VERSION 5.7 ;
  NOWIREEXTENSIONATPIN ON ;
  DIVIDERCHAR "/" ;
  BUSBITCHARS "[]" ;
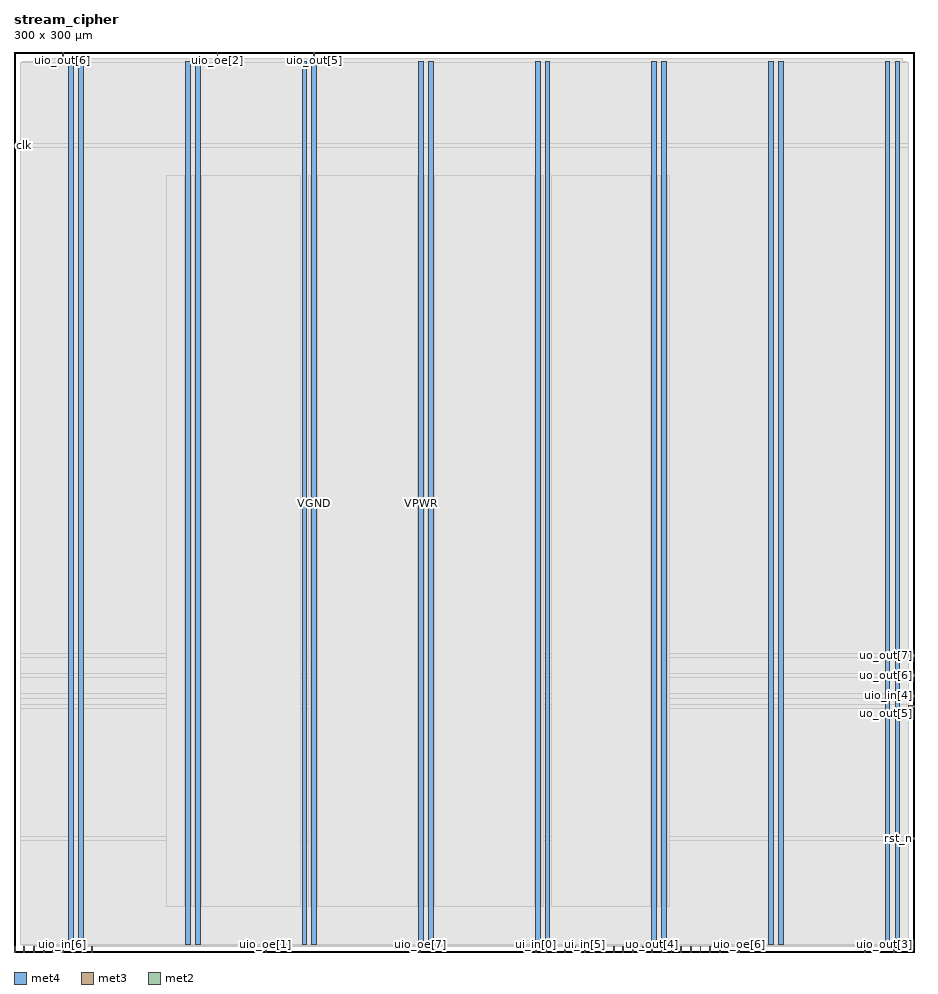
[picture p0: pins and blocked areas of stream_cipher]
MACRO stream_cipher
  CLASS BLOCK ;
  FOREIGN stream_cipher ;
  ORIGIN 0.000 0.000 ;
  SIZE 300.000 BY 300.000 ;
  PIN VGND
    DIRECTION INOUT ;
    USE GROUND ;
    PORT
      LAYER met4 ;
        RECT 21.580 2.480 23.180 296.720 ;
    END
    PORT
      LAYER met4 ;
        RECT 60.450 2.480 62.050 296.720 ;
    END
    PORT
      LAYER met4 ;
        RECT 99.320 2.480 100.920 296.720 ;
    END
    PORT
      LAYER met4 ;
        RECT 138.190 2.480 139.790 296.720 ;
    END
    PORT
      LAYER met4 ;
        RECT 177.060 2.480 178.660 296.720 ;
    END
    PORT
      LAYER met4 ;
        RECT 215.930 2.480 217.530 296.720 ;
    END
    PORT
      LAYER met4 ;
        RECT 254.800 2.480 256.400 296.720 ;
    END
    PORT
      LAYER met4 ;
        RECT 293.670 2.480 295.270 296.720 ;
    END
  END VGND
  PIN VPWR
    DIRECTION INOUT ;
    USE POWER ;
    PORT
      LAYER met4 ;
        RECT 18.280 2.480 19.880 296.720 ;
    END
    PORT
      LAYER met4 ;
        RECT 57.150 2.480 58.750 296.720 ;
    END
    PORT
      LAYER met4 ;
        RECT 96.020 2.480 97.620 296.720 ;
    END
    PORT
      LAYER met4 ;
        RECT 134.890 2.480 136.490 296.720 ;
    END
    PORT
      LAYER met4 ;
        RECT 173.760 2.480 175.360 296.720 ;
    END
    PORT
      LAYER met4 ;
        RECT 212.630 2.480 214.230 296.720 ;
    END
    PORT
      LAYER met4 ;
        RECT 251.500 2.480 253.100 296.720 ;
    END
    PORT
      LAYER met4 ;
        RECT 290.370 2.480 291.970 296.720 ;
    END
  END VPWR
  PIN clk
    DIRECTION INPUT ;
    USE SIGNAL ;
    ANTENNAGATEAREA 0.852000 ;
    PORT
      LAYER met3 ;
        RECT 0.000 268.640 2.000 269.240 ;
    END
  END clk
  PIN ena
    DIRECTION INPUT ;
    USE SIGNAL ;
    PORT
      LAYER met2 ;
        RECT 3.310 0.000 3.590 2.000 ;
    END
  END ena
  PIN rst_n
    DIRECTION INPUT ;
    USE SIGNAL ;
    ANTENNAGATEAREA 0.196500 ;
    PORT
      LAYER met3 ;
        RECT 298.000 37.440 300.000 38.040 ;
    END
  END rst_n
  PIN ui_in[0]
    DIRECTION INPUT ;
    USE SIGNAL ;
    ANTENNAGATEAREA 0.196500 ;
    PORT
      LAYER met2 ;
        RECT 173.970 0.000 174.250 2.000 ;
    END
  END ui_in[0]
  PIN ui_in[1]
    DIRECTION INPUT ;
    USE SIGNAL ;
    ANTENNAGATEAREA 0.196500 ;
    PORT
      LAYER met2 ;
        RECT 180.410 0.000 180.690 2.000 ;
    END
  END ui_in[1]
  PIN ui_in[2]
    DIRECTION INPUT ;
    USE SIGNAL ;
    ANTENNAGATEAREA 0.196500 ;
    PORT
      LAYER met2 ;
        RECT 199.730 0.000 200.010 2.000 ;
    END
  END ui_in[2]
  PIN ui_in[3]
    DIRECTION INPUT ;
    USE SIGNAL ;
    ANTENNAGATEAREA 0.196500 ;
    PORT
      LAYER met2 ;
        RECT 177.190 0.000 177.470 2.000 ;
    END
  END ui_in[3]
  PIN ui_in[4]
    DIRECTION INPUT ;
    USE SIGNAL ;
    ANTENNAGATEAREA 0.196500 ;
    PORT
      LAYER met2 ;
        RECT 183.630 0.000 183.910 2.000 ;
    END
  END ui_in[4]
  PIN ui_in[5]
    DIRECTION INPUT ;
    USE SIGNAL ;
    ANTENNAGATEAREA 0.196500 ;
    PORT
      LAYER met2 ;
        RECT 190.070 0.000 190.350 2.000 ;
    END
  END ui_in[5]
  PIN ui_in[6]
    DIRECTION INPUT ;
    USE SIGNAL ;
    ANTENNAGATEAREA 0.196500 ;
    PORT
      LAYER met2 ;
        RECT 193.290 0.000 193.570 2.000 ;
    END
  END ui_in[6]
  PIN ui_in[7]
    DIRECTION INPUT ;
    USE SIGNAL ;
    ANTENNAGATEAREA 0.196500 ;
    PORT
      LAYER met2 ;
        RECT 196.510 0.000 196.790 2.000 ;
    END
  END ui_in[7]
  PIN uio_in[0]
    DIRECTION INPUT ;
    USE SIGNAL ;
    ANTENNAGATEAREA 0.196500 ;
    PORT
      LAYER met2 ;
        RECT 225.490 0.000 225.770 2.000 ;
    END
  END uio_in[0]
  PIN uio_in[1]
    DIRECTION INPUT ;
    USE SIGNAL ;
    PORT
      LAYER met2 ;
        RECT 22.630 0.000 22.910 2.000 ;
    END
  END uio_in[1]
  PIN uio_in[2]
    DIRECTION INPUT ;
    USE SIGNAL ;
    PORT
      LAYER met2 ;
        RECT 0.090 0.000 0.370 2.000 ;
    END
  END uio_in[2]
  PIN uio_in[3]
    DIRECTION INPUT ;
    USE SIGNAL ;
    ANTENNAGATEAREA 0.196500 ;
    PORT
      LAYER met2 ;
        RECT 219.050 0.000 219.330 2.000 ;
    END
  END uio_in[3]
  PIN uio_in[4]
    DIRECTION INPUT ;
    USE SIGNAL ;
    ANTENNAGATEAREA 0.196500 ;
    PORT
      LAYER met3 ;
        RECT 298.000 85.040 300.000 85.640 ;
    END
  END uio_in[4]
  PIN uio_in[5]
    DIRECTION INPUT ;
    USE SIGNAL ;
    ANTENNAGATEAREA 0.196500 ;
    PORT
      LAYER met2 ;
        RECT 222.270 0.000 222.550 2.000 ;
    END
  END uio_in[5]
  PIN uio_in[6]
    DIRECTION INPUT ;
    USE SIGNAL ;
    PORT
      LAYER met2 ;
        RECT 16.190 0.000 16.470 2.000 ;
    END
  END uio_in[6]
  PIN uio_in[7]
    DIRECTION INPUT ;
    USE SIGNAL ;
    PORT
      LAYER met2 ;
        RECT 19.410 0.000 19.690 2.000 ;
    END
  END uio_in[7]
  PIN uio_oe[0]
    DIRECTION OUTPUT ;
    USE SIGNAL ;
    PORT
      LAYER met2 ;
        RECT 9.750 0.000 10.030 2.000 ;
    END
  END uio_oe[0]
  PIN uio_oe[1]
    DIRECTION OUTPUT ;
    USE SIGNAL ;
    PORT
      LAYER met2 ;
        RECT 83.810 0.000 84.090 2.000 ;
    END
  END uio_oe[1]
  PIN uio_oe[2]
    DIRECTION OUTPUT ;
    USE SIGNAL ;
    PORT
      LAYER met2 ;
        RECT 67.710 298.000 67.990 300.000 ;
    END
  END uio_oe[2]
  PIN uio_oe[3]
    DIRECTION OUTPUT ;
    USE SIGNAL ;
    PORT
      LAYER met2 ;
        RECT 6.530 0.000 6.810 2.000 ;
    END
  END uio_oe[3]
  PIN uio_oe[4]
    DIRECTION OUTPUT ;
    USE SIGNAL ;
    PORT
      LAYER met2 ;
        RECT 12.970 0.000 13.250 2.000 ;
    END
  END uio_oe[4]
  PIN uio_oe[5]
    DIRECTION OUTPUT ;
    USE SIGNAL ;
    PORT
      LAYER met2 ;
        RECT 25.850 0.000 26.130 2.000 ;
    END
  END uio_oe[5]
  PIN uio_oe[6]
    DIRECTION OUTPUT ;
    USE SIGNAL ;
    PORT
      LAYER met2 ;
        RECT 241.590 0.000 241.870 2.000 ;
    END
  END uio_oe[6]
  PIN uio_oe[7]
    DIRECTION OUTPUT ;
    USE SIGNAL ;
    PORT
      LAYER met2 ;
        RECT 135.330 0.000 135.610 2.000 ;
    END
  END uio_oe[7]
  PIN uio_out[0]
    DIRECTION OUTPUT ;
    USE SIGNAL ;
    PORT
      LAYER met2 ;
        RECT 283.450 0.000 283.730 2.000 ;
    END
  END uio_out[0]
  PIN uio_out[1]
    DIRECTION OUTPUT ;
    USE SIGNAL ;
    ANTENNADIFFAREA 0.445500 ;
    PORT
      LAYER met2 ;
        RECT 231.930 0.000 232.210 2.000 ;
    END
  END uio_out[1]
  PIN uio_out[2]
    DIRECTION OUTPUT ;
    USE SIGNAL ;
    ANTENNADIFFAREA 0.445500 ;
    PORT
      LAYER met2 ;
        RECT 235.150 0.000 235.430 2.000 ;
    END
  END uio_out[2]
  PIN uio_out[3]
    DIRECTION OUTPUT ;
    USE SIGNAL ;
    PORT
      LAYER met2 ;
        RECT 293.110 0.000 293.390 2.000 ;
    END
  END uio_out[3]
  PIN uio_out[4]
    DIRECTION OUTPUT ;
    USE SIGNAL ;
    PORT
      LAYER met2 ;
        RECT 228.710 0.000 228.990 2.000 ;
    END
  END uio_out[4]
  PIN uio_out[5]
    DIRECTION OUTPUT ;
    USE SIGNAL ;
    PORT
      LAYER met2 ;
        RECT 99.910 298.000 100.190 300.000 ;
    END
  END uio_out[5]
  PIN uio_out[6]
    DIRECTION OUTPUT ;
    USE SIGNAL ;
    PORT
      LAYER met2 ;
        RECT 16.190 298.000 16.470 300.000 ;
    END
  END uio_out[6]
  PIN uio_out[7]
    DIRECTION OUTPUT ;
    USE SIGNAL ;
    PORT
      LAYER met2 ;
        RECT 186.850 0.000 187.130 2.000 ;
    END
  END uio_out[7]
  PIN uo_out[0]
    DIRECTION OUTPUT ;
    USE SIGNAL ;
    ANTENNAGATEAREA 0.126000 ;
    ANTENNADIFFAREA 0.891000 ;
    PORT
      LAYER met2 ;
        RECT 202.950 0.000 203.230 2.000 ;
    END
  END uo_out[0]
  PIN uo_out[1]
    DIRECTION OUTPUT ;
    USE SIGNAL ;
    ANTENNAGATEAREA 0.126000 ;
    ANTENNADIFFAREA 0.891000 ;
    PORT
      LAYER met2 ;
        RECT 209.390 0.000 209.670 2.000 ;
    END
  END uo_out[1]
  PIN uo_out[2]
    DIRECTION OUTPUT ;
    USE SIGNAL ;
    ANTENNAGATEAREA 0.126000 ;
    ANTENNADIFFAREA 0.891000 ;
    PORT
      LAYER met2 ;
        RECT 215.830 0.000 216.110 2.000 ;
    END
  END uo_out[2]
  PIN uo_out[3]
    DIRECTION OUTPUT ;
    USE SIGNAL ;
    ANTENNAGATEAREA 0.126000 ;
    ANTENNADIFFAREA 0.891000 ;
    PORT
      LAYER met2 ;
        RECT 206.170 0.000 206.450 2.000 ;
    END
  END uo_out[3]
  PIN uo_out[4]
    DIRECTION OUTPUT ;
    USE SIGNAL ;
    ANTENNAGATEAREA 0.126000 ;
    ANTENNADIFFAREA 0.891000 ;
    PORT
      LAYER met2 ;
        RECT 212.610 0.000 212.890 2.000 ;
    END
  END uo_out[4]
  PIN uo_out[5]
    DIRECTION OUTPUT ;
    USE SIGNAL ;
    ANTENNAGATEAREA 0.126000 ;
    ANTENNADIFFAREA 0.891000 ;
    PORT
      LAYER met3 ;
        RECT 298.000 81.640 300.000 82.240 ;
    END
  END uo_out[5]
  PIN uo_out[6]
    DIRECTION OUTPUT ;
    USE SIGNAL ;
    ANTENNAGATEAREA 0.126000 ;
    ANTENNADIFFAREA 0.891000 ;
    PORT
      LAYER met3 ;
        RECT 298.000 91.840 300.000 92.440 ;
    END
  END uo_out[6]
  PIN uo_out[7]
    DIRECTION OUTPUT ;
    USE SIGNAL ;
    ANTENNAGATEAREA 0.126000 ;
    ANTENNADIFFAREA 0.891000 ;
    PORT
      LAYER met3 ;
        RECT 298.000 98.640 300.000 99.240 ;
    END
  END uo_out[7]
  OBS
      LAYER nwell ;
        RECT 2.570 2.635 297.350 296.565 ;
      LAYER li1 ;
        RECT 2.760 2.635 297.160 296.565 ;
      LAYER met1 ;
        RECT 2.760 2.080 297.460 296.720 ;
      LAYER met2 ;
        RECT 6.540 297.720 15.910 298.000 ;
        RECT 16.750 297.720 67.430 298.000 ;
        RECT 68.270 297.720 99.630 298.000 ;
        RECT 100.470 297.720 296.140 298.000 ;
        RECT 6.540 2.280 296.140 297.720 ;
        RECT 7.090 2.000 9.470 2.280 ;
        RECT 10.310 2.000 12.690 2.280 ;
        RECT 13.530 2.000 15.910 2.280 ;
        RECT 16.750 2.000 19.130 2.280 ;
        RECT 19.970 2.000 22.350 2.280 ;
        RECT 23.190 2.000 25.570 2.280 ;
        RECT 26.410 2.000 83.530 2.280 ;
        RECT 84.370 2.000 135.050 2.280 ;
        RECT 135.890 2.000 173.690 2.280 ;
        RECT 174.530 2.000 176.910 2.280 ;
        RECT 177.750 2.000 180.130 2.280 ;
        RECT 180.970 2.000 183.350 2.280 ;
        RECT 184.190 2.000 186.570 2.280 ;
        RECT 187.410 2.000 189.790 2.280 ;
        RECT 190.630 2.000 193.010 2.280 ;
        RECT 193.850 2.000 196.230 2.280 ;
        RECT 197.070 2.000 199.450 2.280 ;
        RECT 200.290 2.000 202.670 2.280 ;
        RECT 203.510 2.000 205.890 2.280 ;
        RECT 206.730 2.000 209.110 2.280 ;
        RECT 209.950 2.000 212.330 2.280 ;
        RECT 213.170 2.000 215.550 2.280 ;
        RECT 216.390 2.000 218.770 2.280 ;
        RECT 219.610 2.000 221.990 2.280 ;
        RECT 222.830 2.000 225.210 2.280 ;
        RECT 226.050 2.000 228.430 2.280 ;
        RECT 229.270 2.000 231.650 2.280 ;
        RECT 232.490 2.000 234.870 2.280 ;
        RECT 235.710 2.000 241.310 2.280 ;
        RECT 242.150 2.000 283.170 2.280 ;
        RECT 284.010 2.000 292.830 2.280 ;
        RECT 293.670 2.000 296.140 2.280 ;
      LAYER met3 ;
        RECT 2.000 269.640 298.000 296.645 ;
        RECT 2.400 268.240 298.000 269.640 ;
        RECT 2.000 99.640 298.000 268.240 ;
        RECT 2.000 98.240 297.600 99.640 ;
        RECT 2.000 92.840 298.000 98.240 ;
        RECT 2.000 91.440 297.600 92.840 ;
        RECT 2.000 86.040 298.000 91.440 ;
        RECT 2.000 84.640 297.600 86.040 ;
        RECT 2.000 82.640 298.000 84.640 ;
        RECT 2.000 81.240 297.600 82.640 ;
        RECT 2.000 38.440 298.000 81.240 ;
        RECT 2.000 37.040 297.600 38.440 ;
        RECT 2.000 2.555 298.000 37.040 ;
      LAYER met4 ;
        RECT 50.895 15.135 56.750 258.905 ;
        RECT 59.150 15.135 60.050 258.905 ;
        RECT 62.450 15.135 95.620 258.905 ;
        RECT 98.020 15.135 98.920 258.905 ;
        RECT 101.320 15.135 134.490 258.905 ;
        RECT 136.890 15.135 137.790 258.905 ;
        RECT 140.190 15.135 173.360 258.905 ;
        RECT 175.760 15.135 176.660 258.905 ;
        RECT 179.060 15.135 212.230 258.905 ;
        RECT 214.630 15.135 215.530 258.905 ;
        RECT 217.930 15.135 218.665 258.905 ;
  END
END stream_cipher
END LIBRARY

